One B-rep face of a CAD part: STEP entity #1044.
In plain terms, the planar face has unit normal (1, 0, 0).
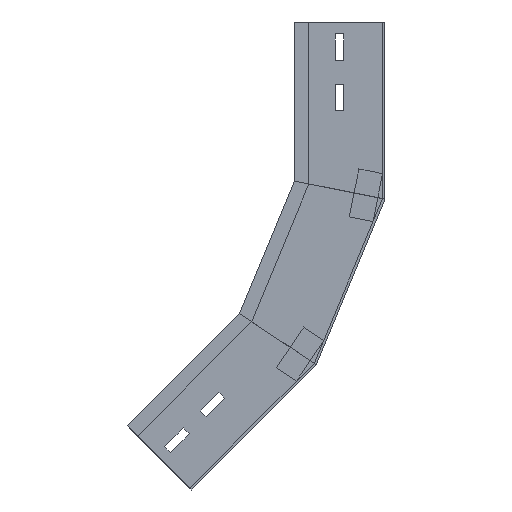
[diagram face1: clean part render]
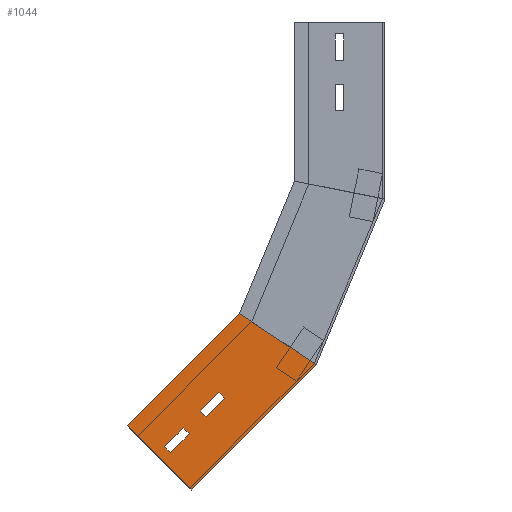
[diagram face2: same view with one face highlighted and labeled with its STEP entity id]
Its self-contained STEP definition (entity closure, numbers rounded to 3 decimals):
#19 = DIRECTION ( 'NONE',  ( 0., -0.981, -0.195 ) ) ;
#23 = DIRECTION ( 'NONE',  ( 0., 0., -1. ) ) ;
#24 = VERTEX_POINT ( 'NONE', #1367 ) ;
#39 = CARTESIAN_POINT ( 'NONE',  ( 0., 41., -51.505 ) ) ;
#112 = CARTESIAN_POINT ( 'NONE',  ( 0., 0., 0. ) ) ;
#114 = CARTESIAN_POINT ( 'NONE',  ( 0., 75., -131.682 ) ) ;
#116 = VECTOR ( 'NONE', #147, 1000. ) ;
#126 = VERTEX_POINT ( 'NONE', #152 ) ;
#129 = VERTEX_POINT ( 'NONE', #655 ) ;
#132 = ORIENTED_EDGE ( 'NONE', *, *, #1113, .T. ) ;
#138 = LINE ( 'NONE', #1183, #308 ) ;
#147 = DIRECTION ( 'NONE',  ( 0., 0., 1. ) ) ;
#152 = CARTESIAN_POINT ( 'NONE',  ( 0., 75., 0. ) ) ;
#222 = LINE ( 'NONE', #238, #646 ) ;
#238 = CARTESIAN_POINT ( 'NONE',  ( 0., 41., -9.835 ) ) ;
#240 = CARTESIAN_POINT ( 'NONE',  ( 0., 41., -51.505 ) ) ;
#246 = VERTEX_POINT ( 'NONE', #489 ) ;
#249 = LINE ( 'NONE', #707, #690 ) ;
#255 = EDGE_CURVE ( 'NONE', #551, #778, #1423, .T. ) ;
#289 = ORIENTED_EDGE ( 'NONE', *, *, #849, .F. ) ;
#293 = LINE ( 'NONE', #39, #309 ) ;
#308 = VECTOR ( 'NONE', #1391, 1000. ) ;
#309 = VECTOR ( 'NONE', #1448, 1000. ) ;
#322 = CARTESIAN_POINT ( 'NONE',  ( 0., 0., 0. ) ) ;
#326 = VERTEX_POINT ( 'NONE', #933 ) ;
#339 = EDGE_CURVE ( 'NONE', #917, #551, #1164, .T. ) ;
#366 = CARTESIAN_POINT ( 'NONE',  ( 0., 34., -51.505 ) ) ;
#374 = EDGE_CURVE ( 'NONE', #326, #246, #249, .T. ) ;
#382 = DIRECTION ( 'NONE',  ( 0., 1., 0. ) ) ;
#398 = LINE ( 'NONE', #857, #496 ) ;
#407 = EDGE_CURVE ( 'NONE', #24, #326, #138, .T. ) ;
#429 = FACE_OUTER_BOUND ( 'NONE', #1275, .T. ) ;
#449 = DIRECTION ( 'NONE',  ( 0., 0., 1. ) ) ;
#458 = ORIENTED_EDGE ( 'NONE', *, *, #705, .T. ) ;
#488 = ORIENTED_EDGE ( 'NONE', *, *, #803, .T. ) ;
#489 = CARTESIAN_POINT ( 'NONE',  ( 0., 34., -9.835 ) ) ;
#496 = VECTOR ( 'NONE', #864, 1000. ) ;
#506 = ORIENTED_EDGE ( 'NONE', *, *, #638, .F. ) ;
#509 = ORIENTED_EDGE ( 'NONE', *, *, #374, .T. ) ;
#518 = DIRECTION ( 'NONE',  ( 0., -1., 0. ) ) ;
#549 = ORIENTED_EDGE ( 'NONE', *, *, #550, .F. ) ;
#550 = EDGE_CURVE ( 'NONE', #1264, #1413, #1297, .T. ) ;
#551 = VERTEX_POINT ( 'NONE', #1449 ) ;
#566 = ORIENTED_EDGE ( 'NONE', *, *, #793, .T. ) ;
#587 = DIRECTION ( 'NONE',  ( 0., 1., 0. ) ) ;
#588 = ORIENTED_EDGE ( 'NONE', *, *, #953, .T. ) ;
#638 = EDGE_CURVE ( 'NONE', #129, #126, #937, .T. ) ;
#646 = VECTOR ( 'NONE', #1041, 1000. ) ;
#651 = ORIENTED_EDGE ( 'NONE', *, *, #255, .T. ) ;
#655 = CARTESIAN_POINT ( 'NONE',  ( 0., 0., 0. ) ) ;
#674 = VERTEX_POINT ( 'NONE', #1274 ) ;
#690 = VECTOR ( 'NONE', #853, 1000. ) ;
#691 = CARTESIAN_POINT ( 'NONE',  ( 0., 0., -146.6 ) ) ;
#705 = EDGE_CURVE ( 'NONE', #129, #1413, #806, .T. ) ;
#707 = CARTESIAN_POINT ( 'NONE',  ( 0., 34., -9.835 ) ) ;
#756 = LINE ( 'NONE', #1008, #1123 ) ;
#769 = AXIS2_PLACEMENT_3D ( 'NONE', #322, #804, #449 ) ;
#778 = VERTEX_POINT ( 'NONE', #240 ) ;
#788 = VECTOR ( 'NONE', #23, 1000. ) ;
#793 = EDGE_CURVE ( 'NONE', #674, #917, #972, .T. ) ;
#803 = EDGE_CURVE ( 'NONE', #778, #674, #293, .T. ) ;
#804 = DIRECTION ( 'NONE',  ( -1., 0., 0. ) ) ;
#806 = LINE ( 'NONE', #1168, #788 ) ;
#809 = EDGE_LOOP ( 'NONE', ( #651, #488, #566, #979 ) ) ;
#849 = EDGE_CURVE ( 'NONE', #126, #1264, #398, .T. ) ;
#852 = CARTESIAN_POINT ( 'NONE',  ( 0., 34., -73.505 ) ) ;
#853 = DIRECTION ( 'NONE',  ( 0., 0., 1. ) ) ;
#857 = CARTESIAN_POINT ( 'NONE',  ( 0., 75., 0. ) ) ;
#864 = DIRECTION ( 'NONE',  ( 0., 0., -1. ) ) ;
#887 = VECTOR ( 'NONE', #19, 1000. ) ;
#894 = FACE_BOUND ( 'NONE', #1065, .T. ) ;
#917 = VERTEX_POINT ( 'NONE', #852 ) ;
#933 = CARTESIAN_POINT ( 'NONE',  ( 0., 34., -31.835 ) ) ;
#937 = LINE ( 'NONE', #112, #1256 ) ;
#953 = EDGE_CURVE ( 'NONE', #246, #1101, #756, .T. ) ;
#972 = LINE ( 'NONE', #1075, #1033 ) ;
#979 = ORIENTED_EDGE ( 'NONE', *, *, #339, .T. ) ;
#983 = VECTOR ( 'NONE', #382, 1000. ) ;
#1008 = CARTESIAN_POINT ( 'NONE',  ( 0., 41., -9.835 ) ) ;
#1033 = VECTOR ( 'NONE', #518, 1000. ) ;
#1041 = DIRECTION ( 'NONE',  ( 0., 0., -1. ) ) ;
#1044 = ADVANCED_FACE ( 'NONE', ( #1472, #429, #894 ), #1366, .F. ) ;
#1055 = CARTESIAN_POINT ( 'NONE',  ( 0., 28.051, -141.02 ) ) ;
#1065 = EDGE_LOOP ( 'NONE', ( #588, #132, #1482, #509 ) ) ;
#1075 = CARTESIAN_POINT ( 'NONE',  ( 0., 41., -73.505 ) ) ;
#1101 = VERTEX_POINT ( 'NONE', #1263 ) ;
#1113 = EDGE_CURVE ( 'NONE', #1101, #24, #222, .T. ) ;
#1123 = VECTOR ( 'NONE', #1128, 1000. ) ;
#1128 = DIRECTION ( 'NONE',  ( 0., 1., 0. ) ) ;
#1164 = LINE ( 'NONE', #366, #116 ) ;
#1168 = CARTESIAN_POINT ( 'NONE',  ( 0., 0., 0. ) ) ;
#1183 = CARTESIAN_POINT ( 'NONE',  ( 0., 41., -31.835 ) ) ;
#1256 = VECTOR ( 'NONE', #587, 1000. ) ;
#1263 = CARTESIAN_POINT ( 'NONE',  ( 0., 41., -9.835 ) ) ;
#1264 = VERTEX_POINT ( 'NONE', #114 ) ;
#1274 = CARTESIAN_POINT ( 'NONE',  ( 0., 41., -73.505 ) ) ;
#1275 = EDGE_LOOP ( 'NONE', ( #289, #506, #458, #549 ) ) ;
#1297 = LINE ( 'NONE', #1055, #887 ) ;
#1366 = PLANE ( 'NONE',  #769 ) ;
#1367 = CARTESIAN_POINT ( 'NONE',  ( 0., 41., -31.835 ) ) ;
#1391 = DIRECTION ( 'NONE',  ( 0., -1., 0. ) ) ;
#1413 = VERTEX_POINT ( 'NONE', #691 ) ;
#1423 = LINE ( 'NONE', #1436, #983 ) ;
#1436 = CARTESIAN_POINT ( 'NONE',  ( 0., 41., -51.505 ) ) ;
#1448 = DIRECTION ( 'NONE',  ( 0., 0., -1. ) ) ;
#1449 = CARTESIAN_POINT ( 'NONE',  ( 0., 34., -51.505 ) ) ;
#1472 = FACE_BOUND ( 'NONE', #809, .T. ) ;
#1482 = ORIENTED_EDGE ( 'NONE', *, *, #407, .T. ) ;
